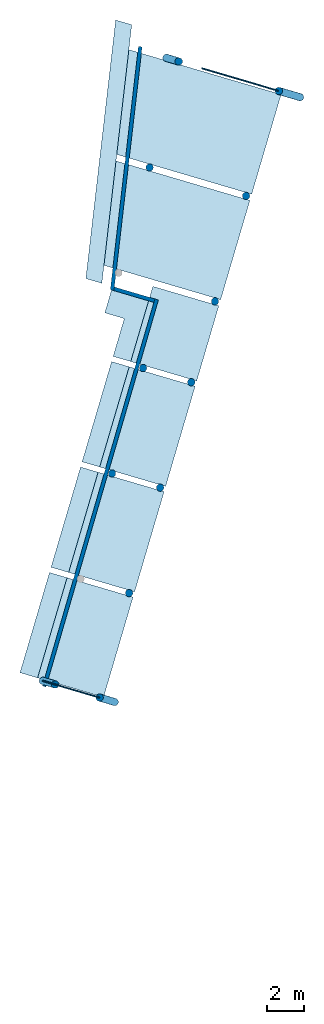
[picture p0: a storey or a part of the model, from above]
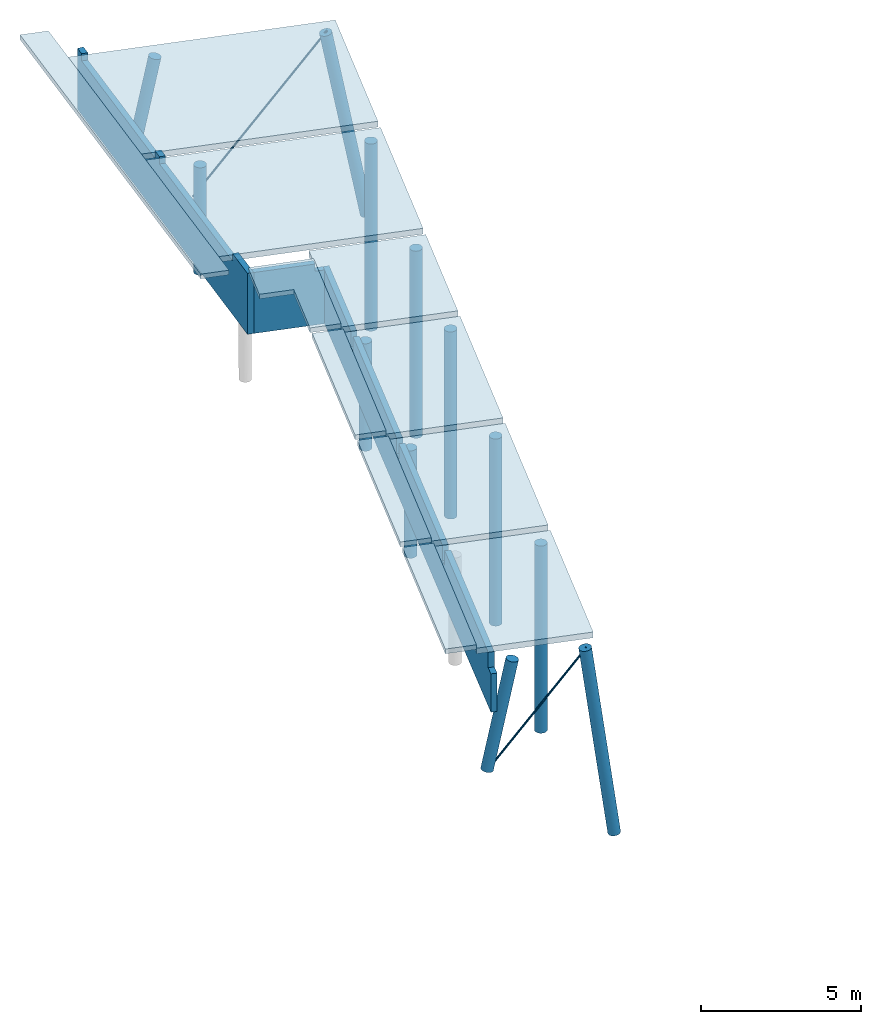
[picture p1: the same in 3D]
Properties of the parts of a building model (IFC2X3)

# File
Description: ViewDefinition [CoordinationView_V2.0, QuantityTakeOffAddOnView], RevitIdentifiers [ContentGUID: 5815a2d3-4dd0-42b5-9a26-895047bd95dd, VersionGUID: b3478333-63a0-4f75-ae6b-75b3e065c498, NumberOfSaves: 117], CoordinateReference [CoordinateBase: Shared Coordinates, ProjectSite: Standard]
File name: 10250977-001 Espevær_kai.ifc
Time: 2026-08-18T09:46:04+01:00
Written by: ODA SDAI 24.12
Made in: Autodesk Revit 25.4.41.14 (ENU) - IFC 25.4.4.0

# IfcProject, 10250977-001
LongName: Espevær kai; Phase: Foreløpig

# IfcSite, SiteName
RefLatitude: 42, 24, 53, 508911; RefLongitude: -71, -15, -29, -58837; RefElevation: 0 mm

# IfcBuilding, Building Name
LongName: Building Name
Pset_BuildingCommon - NumberOfStoreys: 2
Prosjektinformasjon - Revit mal versjon: -; Modellfase: ???; Informasjonsnivå: Informasjonsnivå; Fagområde: -; Modell utarbeidet av: -; Modell kontrollert av: -; Beregning utarbeidet av: Beregning utarbeidet av; Koordinatsystem: ???; Høydedatum: ???; Entreprise: -; Kunde navn: Vestland Fylkeskommune; Prosjekt navn: Espevær kai; Prosjekt nummer: 10250977-001; Levert dato: -

# IfcBuildingStorey: Level:8mm Head (2)
In: Building Name
Pset_AirSideSystemInformation - sets with these values: 2
Name | LongName = Name | Elevation (mm)
NN 2000 | NN 2000 | 3.40151e-10
HAT | HAT | 540

# IfcBeam: Beam KR Solid:KR 70 (2)
In: NN 2000
Type - Pset_BeamCommon - LoadBearing: yes
Type - Armering - F.43 D: 70 mm
Material: Structural Framing Fireproofing
BaseQuantities - CrossSectionArea: 0.00384254 m2
Pset_BeamCommon - IsExternal: no; Reference: KR 70; Span: 5185.4 mm; Slope: 52.5472 deg
Pset_QuantityTakeOff - Reference: KR 70; sets with these values: 2
Egenskaper - D.01 Material: Steel - S355
Name (Beam KR Solid:KR 70:...) | Length (mm) | OuterSurfaceArea (m2) | GrossVolume (m3) | NetVolume (m3)
2086246 | 5251.63 | 1.15489 | 0.0201796 | 0.0202002
2111559 | 7074.13 | 1.55568 | 0.0271826 | 0.0272104

# IfcBeam: Concrete-L-Beam:LB 520x550 (2)
In: HAT
Type - Pset_BeamCommon - LoadBearing: yes
Type - Egenskaper - A.03 Post/kode: 2231; A.04 Forklaring: Betongbjelker
Type - Armering - F.41 B: 350 mm; F.42 C: 200 mm; F.43 D: 300 mm; F.46 H: 650 mm
Classification: 2231 Betongbjelker (Uniformat); Material: Concrete - Cast-in-Place
Pset_BeamCommon - Slope: 0 deg; IsExternal: no; Reference: LB 520x550
Pset_QuantityTakeOff - Reference: LB 520x550; sets with these values: 2
Egenskaper - D.01 Material: Concrete - Cast-in-Place; D.10 Overdekning Topp: 60 mm <60 mm>; D.11 Overdekning Bunn: 60 mm <60 mm>
Name (Concrete-L-Beam:LB 520x550:...) | CrossSectionArea (m2) | NetVolume (m3) | Span (mm)
1908641 | 0.2875 | 1.45187 | 4900 | BaseQuantities - Length: 5049.98 mm; OuterSurfaceArea: 12.12 m2; GrossVolume: 1.45187 m3; Egenskaper - D.12 Overdekning Andre: 60 mm <60 mm>
1915109 | 11.2996 | 2.53236 | 8991.75

# IfcBeam: Concrete-Rectangular-Beam:1000x300 (6)
In: HAT
Type - PredefinedType: BEAM
Type - Pset_BeamCommon - LoadBearing: yes
Type - Egenskaper - A.03 Post/kode: 2231; A.04 Forklaring: Betongbjelker
Type - Armering - F.41 B: 300 mm; F.46 H: 1000 mm
Classification: 2231 Betongbjelker (Uniformat); Material: Concrete - Cast-in-Place
Pset_BeamCommon - Reference: 1000x300; Slope: 0 deg; IsExternal: no
Pset_QuantityTakeOff - Reference: 1000x300; sets with these values: 2
Egenskaper - D.01 Material: Concrete - Cast-in-Place; D.10 Overdekning Topp: 60 mm <60 mm>; D.11 Overdekning Bunn: 60 mm <60 mm>; D.12 Overdekning Andre: 60 mm <60 mm>
Name (Concrete-Rectangular-Beam:1000x300:...) | CrossSectionArea (m2) | NetVolume (m3) | Span (mm)
1844534 | 7.80749 | 1.68973 | 12025
1964607 | 7.90502 | 1.70552 | 6000
1964792 | 7.9049 | 1.70547 | 6000
1964903 | 6.04984 | 1.27496 | 4599.87
1964950 | 7.835 | 1.6845 | 5999.99
1965087 | 7.77258 | 1.67925 | 6200.28

# IfcBeam: DLB:DLB 520x700, DLB:DLB 520x700:1909585
In: HAT
Type - PredefinedType: BEAM
Type - Pset_BeamCommon - LoadBearing: yes
Type - Egenskaper - A.03 Post/kode: 223; A.04 Forklaring: Bjelker
Type - Armering - F.41 B: 300 mm; F.42 C: 200 mm; F.43 D: 300 mm; F.46 H: 650 mm
Classification: 223 Bjelker (Uniformat); Material: Concrete - Cast-in-Place
BaseQuantities - Length: 5054.33 mm; CrossSectionArea: 0.315 m2; OuterSurfaceArea: 13.6467 m2; GrossVolume: 1.59211 m3; NetVolume: 1.59211 m3
Pset_BeamCommon - Slope: 0 deg; IsExternal: no; Reference: DLB 520x700; Span: 5054.33 mm
Pset_QuantityTakeOff - Reference: DLB 520x700; sets with these values: 2
Egenskaper - D.01 Material: Concrete - Cast-in-Place; D.10 Overdekning Topp: 60 mm <60 mm>; D.11 Overdekning Bunn: 60 mm <60 mm>; D.12 Overdekning Andre: 60 mm <60 mm>

# IfcBeam: DLB:DLB 520x700 (2)
In: HAT
Type - Pset_BeamCommon - LoadBearing: yes
Type - Egenskaper - A.03 Post/kode: 223; A.04 Forklaring: Bjelker
Type - Armering - F.41 B: 300 mm; F.42 C: 200 mm; F.43 D: 300 mm; F.46 H: 650 mm
Classification: 223 Bjelker (Uniformat); Material: Concrete - Cast-in-Place
BaseQuantities - CrossSectionArea: 0.315 m2
Pset_BeamCommon - Slope: 0 deg; IsExternal: no; Reference: DLB 520x700
Pset_QuantityTakeOff - Reference: DLB 520x700; sets with these values: 2
Egenskaper - D.01 Material: Concrete - Cast-in-Place; D.10 Overdekning Topp: 60 mm <60 mm>; D.11 Overdekning Bunn: 60 mm <60 mm>; D.12 Overdekning Andre: 60 mm <60 mm>
Name (DLB:DLB 520x700:...) | Length (mm) = Span (mm) | OuterSurfaceArea (m2) | GrossVolume (m3) = NetVolume (m3)
1907945 | 5054.69 | 13.6477 | 1.59223
1914887 | 5054.41 | 13.6469 | 1.59214

# IfcBeam: DLB:DLB 570x750 (2)
In: HAT
Type - Pset_BeamCommon - LoadBearing: yes
Type - Egenskaper - A.03 Post/kode: 223; A.04 Forklaring: Bjelker
Type - Armering - F.41 B: 350 mm; F.42 C: 200 mm; F.43 D: 350 mm; F.46 H: 700 mm
Classification: 223 Bjelker (Uniformat); Material: Concrete - Cast-in-Place
Pset_BeamCommon - Slope: 0 deg; IsExternal: no; Reference: DLB 570x750
Pset_QuantityTakeOff - Reference: DLB 570x750; sets with these values: 2
Egenskaper - D.01 Material: Concrete - Cast-in-Place; D.10 Overdekning Topp: 60 mm <60 mm>; D.11 Overdekning Bunn: 60 mm <60 mm>
Name (DLB:DLB 570x750:...) | CrossSectionArea (m2) | NetVolume (m3) | Span (mm)
1914982 | 11.5848 | 2.95467 | 7823.21
1915049 | 13.0913 | 3.35467 | 8862.16

# IfcBuildingElementProxy: SW Nullpunktsobjekt 9 Fag:SW Nullpunktsobjekt 9 Fag, SW Nullpunktsobjekt 9 Fag:SW Nullpunktsobjekt 9 Fag:515982
In: NN 2000
Type - Material: Sweco grey - base colour
Pset_BuildingElementProxyCommon - Reference: SW Nullpunktsobjekt 9 Fag; sets with these values: 2

# IfcColumn: Concrete-Circular-Column:406 (4)
In: NN 2000
Type - PredefinedType: COLUMN; Material: <Unnamed>, Concrete - Cast-in-Place
Type - Pset_ColumnCommon - LoadBearing: yes
Type - Egenskaper - A.03 Post/kode: 2221; A.04 Forklaring: Betongsøyler
Type - Armering - F.43 D: 406 mm
Classification: 2221 Betongsøyler (Uniformat); Material: Concrete - Cast-in-Place
BaseQuantities - CrossSectionArea: 0.129457 m2
Pset_ColumnCommon - IsExternal: no; Reference: 406
Pset_QuantityTakeOff - Reference: 406; sets with these values: 2
Egenskaper - D.12 Overdekning Andre: 60 mm <60 mm>
Name (Concrete-Circular-Column:406:...) | Length (mm) | OuterSurfaceArea (m2) | GrossVolume (m3) | NetVolume (m3) | Slope (deg)
2067333 | 4163 | 5.30985 | 0.53893 | 0.538931 | 78.7723
2070317 | 7250 | 9.24728 | 0.938564 | 0.938566 | 82.598
2071514 | 7250 | 9.24728 | 0.938564 | 0.93857 | 79.5682
2071748 | 4163 | 5.30985 | 0.53893 | 0.538935 | 78.7723

# IfcColumn: Concrete-Circular-Column:406 (10)
In: NN 2000
Type - PredefinedType: COLUMN; Material: Concrete - Cast-in-Place
Type - Pset_ColumnCommon - LoadBearing: yes
Type - Egenskaper - A.03 Post/kode: 2221; A.04 Forklaring: Betongsøyler
Type - Armering - F.43 D: 406 mm
Classification: 2221 Betongsøyler (Uniformat)
Pset_ColumnCommon - IsExternal: no; Reference: 406
Pset_QuantityTakeOff - Reference: 406; sets with these values: 2
Egenskaper - D.11 Overdekning Bunn: 60 mm <60 mm>; D.12 Overdekning Andre: 60 mm <60 mm>
Name (Concrete-Circular-Column:406:...) | Length (mm) | CrossSectionArea (m2) | OuterSurfaceArea (m2) | GrossVolume (m3) | NetVolume (m3) | D.10 Overdekning Topp | Slope (deg)
1906624 | 7140 | 0.129457 | 9.10697 | 0.924324 | 0.924325 | 60 mm <60 mm>
1906663 | 7140 | 0.129457 | 9.10697 | 0.924324 | 0.924325 | 60 mm <60 mm> | 0
1906686 | 7140 | 0.129457 | 9.10697 | 0.924324 | 0.924325 | 60 mm <60 mm> | 0
1907158 | 7140 | 0.129457 | 9.10697 | 0.924324 | 0.924325 | 60 mm <60 mm> | 0
1907166 | 7140 | 0.129457 | 9.10697 | 0.924324 | 0.924325 | 60 mm <60 mm> | 0
1907476 |  | 2.73977 |  |  | 0.52354 | 60 mm <60 mm>
1907486 | 4100 | 0.129457 | 5.2295 | 0.530774 | 0.530775 | 60 mm <60 mm> | 0
1907496 | 4100 | 0.129457 | 5.2295 | 0.530774 | 0.530775 | 60 mm <60 mm> | 0
1907506 |  | 2.71301 |  |  | 0.507913 | 60 mm <60 mm> | 0
2073970 | 4100 | 0.129457 | 5.2295 | 0.530774 | 0.530775

# IfcOpeningElement: Opening (3)
In: HAT
BaseQuantities - Height: 67.6756 mm; Width: 124.177 mm
Pset_OpeningElementCommon - Reference: Betong 130; sets with these values: 2

# IfcSlab: Floor:Betong 130, Floor:Betong 130:1858483
In: HAT
Type - PredefinedType: FLOOR; Material: Concrete - Cast-in-Place 130 mm
Type - Pset_ReinforcementBarPitchOfSlab - Description: Betongdekke
Type - Egenskaper - A.03 Post/kode: 2511; A.04 Forklaring: Frittbærende dekker, betong; D.01 Material: Concrete - Cast-in-Place
Classification: 2511 Frittbærende dekker, betong (Uniformat)
Pset_QuantityTakeOff - Reference: Betong 130; sets with these values: 2
Pset_SlabCommon - IsExternal: no; LoadBearing: yes; Reference: Betong 130; PitchAngle: 0 deg
Egenskaper - D.10 Overdekning Topp: 60 mm <60 mm>; D.11 Overdekning Bunn: 60 mm <60 mm>
BaseQuantities - Perimeter: 288.953 mm; GrossArea: 21.398 m2; NetArea: 174.97 m2; GrossVolume: 2.78174 m3; NetVolume: 22.7461 m3

# IfcSlab: Floor:Betong 180, Floor:Betong 180:1962296
In: NN 2000
Type - PredefinedType: FLOOR; Material: Concrete - Cast-in-Place 180 mm
Type - Pset_ReinforcementBarPitchOfSlab - Description: Betongdekke
Type - Egenskaper - A.03 Post/kode: 2511; A.04 Forklaring: Frittbærende dekker, betong; D.01 Material: Concrete - Cast-in-Place
Classification: 2511 Frittbærende dekker, betong (Uniformat)
Pset_QuantityTakeOff - Reference: Betong 180; sets with these values: 2
Pset_SlabCommon - IsExternal: no; LoadBearing: yes; PitchAngle: 0 deg; Reference: Betong 180
Egenskaper - D.10 Overdekning Topp: 60 mm <60 mm>; D.11 Overdekning Bunn: 60 mm <60 mm>; D.12 Overdekning Andre: 60 mm <60 mm>
BaseQuantities - Perimeter: 99.2227 mm; GrossArea: 12.7873 m2; NetArea: 12.7873 m2; GrossVolume: 2.30172 m3; NetVolume: 2.30172 m3

# IfcSlab: Floor:Prefab 220 (6)
In: NN 2000
Type - PredefinedType: FLOOR; Material: Concrete - Cast-in-Place 220 mm
Type - Pset_ReinforcementBarPitchOfSlab - Description: Betongdekke
Type - Egenskaper - A.03 Post/kode: 2511; A.04 Forklaring: Frittbærende dekker, betong; D.01 Material: Concrete - Cast-in-Place
Classification: 2511 Frittbærende dekker, betong (Uniformat)
Pset_QuantityTakeOff - Reference: Prefab 220; sets with these values: 2
Pset_SlabCommon - IsExternal: no; LoadBearing: yes; PitchAngle: 0 deg; Reference: Prefab 220
Egenskaper - D.10 Overdekning Topp: 60 mm <60 mm>; D.11 Overdekning Bunn: 60 mm <60 mm>
BaseQuantities - Perimeter: 414.04 mm; NetArea: 166.888 m2; NetVolume: 36.7153 m3
Name (Floor:Prefab 220:...) | GrossArea (m2) | GrossVolume (m3)
1907709 | 21.399 | 4.70778
1907709:2 | 21.3987 | 4.70771
1907709:3 | 21.3958 | 4.70708
1907709:4 | 16.0494 | 3.53086
1907709:5 | 40.2788 | 8.86134
1907709:6 | 46.366 | 10.2005

# IfcSlab: Floor:Påstøp 180, Floor:Påstøp 180:2078352
In: NN 2000
Type - PredefinedType: FLOOR; Material: Concrete - Cast-in-Place 180 mm
Type - Pset_ReinforcementBarPitchOfSlab - Description: Betongdekke
Type - Egenskaper - A.03 Post/kode: 2511; A.04 Forklaring: Frittbærende dekker, betong; D.01 Material: Concrete - Cast-in-Place
Classification: 2511 Frittbærende dekker, betong (Uniformat)
Pset_QuantityTakeOff - Reference: Påstøp 180; sets with these values: 2
Pset_SlabCommon - IsExternal: no; LoadBearing: yes; PitchAngle: 0 deg; Reference: Påstøp 180
Egenskaper - D.10 Overdekning Topp: 60 mm <60 mm>; D.11 Overdekning Bunn: 60 mm <60 mm>; D.12 Overdekning Andre: 60 mm <60 mm>
BaseQuantities - Width: 1000 mm; Perimeter: 155.891 mm; GrossArea: 5.69984 m2; NetArea: 22.4118 m2; GrossVolume: 1.02597 m3; NetVolume: 4.03412 m3

# IfcWallStandardCase: Basic Wall:Natursteinsmur (3)
In: NN 2000
Type - PredefinedType: STANDARD; Material: Sprengstein 200 mm
Type - Egenskaper - A.03 Post/kode: 2411; A.04 Forklaring: Bærende innervegger betong; D.01 Material: Sprengstein
Classification: 2411 Bærende innervegger betong (Uniformat)
BaseQuantities - Width: 200 mm
Pset_QuantityTakeOff - Reference: Natursteinsmur; sets with these values: 2
Pset_WallCommon - IsExternal: no; LoadBearing: yes; Reference: Natursteinsmur; ExtendToStructure: yes
Egenskaper - D.12 Overdekning Andre: 35 mm <35 mm>; D.13 Overdekning Utside: 35 mm <35 mm>; D.14 Overdekning Innside: 35 mm <35 mm>
Name (Basic Wall:Natursteinsmur:...) | Height (mm) | Length (mm) | GrossFootprintArea (m2) | GrossVolume (m3) | GrossSideArea (m2) = NetSideArea (m2) | NetVolume (m3)
1861533 | 2325 | 13396.3 | 2.6758 | 5.59714 | 27.9857 | 5.58909
1882903 | 2050 | 22000.4 | 4.40002 | 8.87384 | 44.3692 | 8.87373
1884239 | 2325 | 2307.18 | 0.457903 | 1.05601 | 5.28004 | 1.04811
